One B-rep face of a CAD part: STEP entity #47.
In plain terms, the planar face has unit normal (-1, 0, 0).
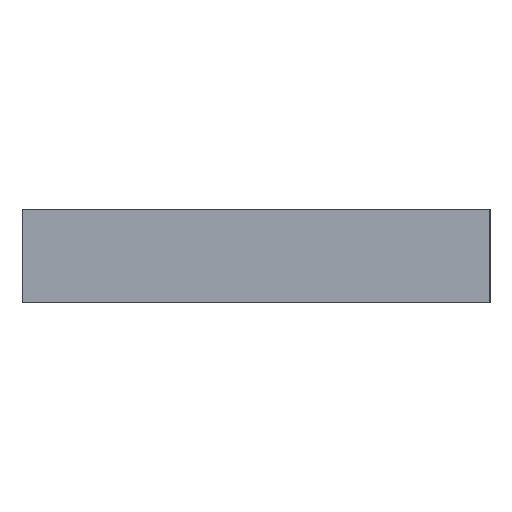
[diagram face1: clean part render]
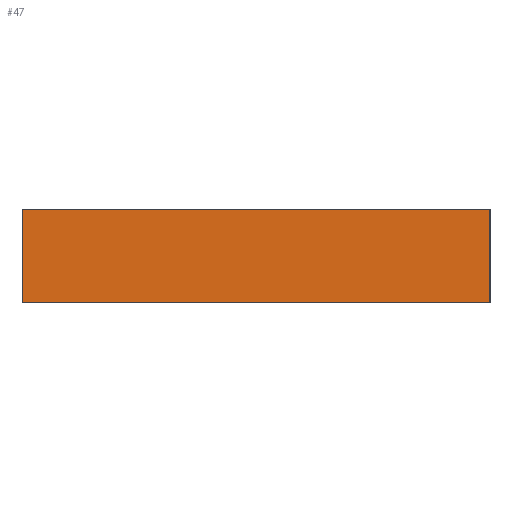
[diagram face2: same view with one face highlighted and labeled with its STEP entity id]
Its self-contained STEP definition (entity closure, numbers rounded to 3 decimals):
#47 = ADVANCED_FACE('',(#48),#62,.F.);
#48 = FACE_BOUND('',#49,.F.);
#49 = EDGE_LOOP('',(#50,#85,#113,#141));
#50 = ORIENTED_EDGE('',*,*,#51,.F.);
#51 = EDGE_CURVE('',#52,#54,#56,.T.);
#52 = VERTEX_POINT('',#53);
#53 = CARTESIAN_POINT('',(-23.167,-13.5,23.875));
#54 = VERTEX_POINT('',#55);
#55 = CARTESIAN_POINT('',(-23.167,-13.5,24.475));
#56 = SURFACE_CURVE('',#57,(#61,#73),.PCURVE_S1.);
#57 = LINE('',#58,#59);
#58 = CARTESIAN_POINT('',(-23.167,-13.5,23.875));
#59 = VECTOR('',#60,1.);
#60 = DIRECTION('',(0.,0.,1.));
#61 = PCURVE('',#62,#67);
#62 = PLANE('',#63);
#63 = AXIS2_PLACEMENT_3D('',#64,#65,#66);
#64 = CARTESIAN_POINT('',(-23.167,-13.5,23.875));
#65 = DIRECTION('',(1.,0.,0.));
#66 = DIRECTION('',(0.,0.,1.));
#67 = DEFINITIONAL_REPRESENTATION('',(#68),#72);
#68 = LINE('',#69,#70);
#69 = CARTESIAN_POINT('',(0.,0.));
#70 = VECTOR('',#71,1.);
#71 = DIRECTION('',(1.,0.));
#72 = ( GEOMETRIC_REPRESENTATION_CONTEXT(2) 
PARAMETRIC_REPRESENTATION_CONTEXT() REPRESENTATION_CONTEXT('2D SPACE',''
  ) );
#73 = PCURVE('',#74,#79);
#74 = PLANE('',#75);
#75 = AXIS2_PLACEMENT_3D('',#76,#77,#78);
#76 = CARTESIAN_POINT('',(-23.167,-13.5,23.875));
#77 = DIRECTION('',(0.,1.,0.));
#78 = DIRECTION('',(0.,0.,1.));
#79 = DEFINITIONAL_REPRESENTATION('',(#80),#84);
#80 = LINE('',#81,#82);
#81 = CARTESIAN_POINT('',(0.,0.));
#82 = VECTOR('',#83,1.);
#83 = DIRECTION('',(1.,0.));
#84 = ( GEOMETRIC_REPRESENTATION_CONTEXT(2) 
PARAMETRIC_REPRESENTATION_CONTEXT() REPRESENTATION_CONTEXT('2D SPACE',''
  ) );
#85 = ORIENTED_EDGE('',*,*,#86,.T.);
#86 = EDGE_CURVE('',#52,#87,#89,.T.);
#87 = VERTEX_POINT('',#88);
#88 = CARTESIAN_POINT('',(-23.167,-10.5,23.875));
#89 = SURFACE_CURVE('',#90,(#94,#101),.PCURVE_S1.);
#90 = LINE('',#91,#92);
#91 = CARTESIAN_POINT('',(-23.167,-13.5,23.875));
#92 = VECTOR('',#93,1.);
#93 = DIRECTION('',(0.,1.,0.));
#94 = PCURVE('',#62,#95);
#95 = DEFINITIONAL_REPRESENTATION('',(#96),#100);
#96 = LINE('',#97,#98);
#97 = CARTESIAN_POINT('',(0.,0.));
#98 = VECTOR('',#99,1.);
#99 = DIRECTION('',(0.,-1.));
#100 = ( GEOMETRIC_REPRESENTATION_CONTEXT(2) 
PARAMETRIC_REPRESENTATION_CONTEXT() REPRESENTATION_CONTEXT('2D SPACE',''
  ) );
#101 = PCURVE('',#102,#107);
#102 = PLANE('',#103);
#103 = AXIS2_PLACEMENT_3D('',#104,#105,#106);
#104 = CARTESIAN_POINT('',(-23.167,-13.5,23.875));
#105 = DIRECTION('',(0.,0.,1.));
#106 = DIRECTION('',(1.,0.,0.));
#107 = DEFINITIONAL_REPRESENTATION('',(#108),#112);
#108 = LINE('',#109,#110);
#109 = CARTESIAN_POINT('',(0.,0.));
#110 = VECTOR('',#111,1.);
#111 = DIRECTION('',(0.,1.));
#112 = ( GEOMETRIC_REPRESENTATION_CONTEXT(2) 
PARAMETRIC_REPRESENTATION_CONTEXT() REPRESENTATION_CONTEXT('2D SPACE',''
  ) );
#113 = ORIENTED_EDGE('',*,*,#114,.T.);
#114 = EDGE_CURVE('',#87,#115,#117,.T.);
#115 = VERTEX_POINT('',#116);
#116 = CARTESIAN_POINT('',(-23.167,-10.5,24.475));
#117 = SURFACE_CURVE('',#118,(#122,#129),.PCURVE_S1.);
#118 = LINE('',#119,#120);
#119 = CARTESIAN_POINT('',(-23.167,-10.5,23.875));
#120 = VECTOR('',#121,1.);
#121 = DIRECTION('',(0.,0.,1.));
#122 = PCURVE('',#62,#123);
#123 = DEFINITIONAL_REPRESENTATION('',(#124),#128);
#124 = LINE('',#125,#126);
#125 = CARTESIAN_POINT('',(0.,-3.));
#126 = VECTOR('',#127,1.);
#127 = DIRECTION('',(1.,0.));
#128 = ( GEOMETRIC_REPRESENTATION_CONTEXT(2) 
PARAMETRIC_REPRESENTATION_CONTEXT() REPRESENTATION_CONTEXT('2D SPACE',''
  ) );
#129 = PCURVE('',#130,#135);
#130 = PLANE('',#131);
#131 = AXIS2_PLACEMENT_3D('',#132,#133,#134);
#132 = CARTESIAN_POINT('',(-23.167,-10.5,23.875));
#133 = DIRECTION('',(0.,1.,0.));
#134 = DIRECTION('',(0.,0.,1.));
#135 = DEFINITIONAL_REPRESENTATION('',(#136),#140);
#136 = LINE('',#137,#138);
#137 = CARTESIAN_POINT('',(0.,0.));
#138 = VECTOR('',#139,1.);
#139 = DIRECTION('',(1.,0.));
#140 = ( GEOMETRIC_REPRESENTATION_CONTEXT(2) 
PARAMETRIC_REPRESENTATION_CONTEXT() REPRESENTATION_CONTEXT('2D SPACE',''
  ) );
#141 = ORIENTED_EDGE('',*,*,#142,.F.);
#142 = EDGE_CURVE('',#54,#115,#143,.T.);
#143 = SURFACE_CURVE('',#144,(#148,#155),.PCURVE_S1.);
#144 = LINE('',#145,#146);
#145 = CARTESIAN_POINT('',(-23.167,-13.5,24.475));
#146 = VECTOR('',#147,1.);
#147 = DIRECTION('',(0.,1.,0.));
#148 = PCURVE('',#62,#149);
#149 = DEFINITIONAL_REPRESENTATION('',(#150),#154);
#150 = LINE('',#151,#152);
#151 = CARTESIAN_POINT('',(0.6,0.));
#152 = VECTOR('',#153,1.);
#153 = DIRECTION('',(0.,-1.));
#154 = ( GEOMETRIC_REPRESENTATION_CONTEXT(2) 
PARAMETRIC_REPRESENTATION_CONTEXT() REPRESENTATION_CONTEXT('2D SPACE',''
  ) );
#155 = PCURVE('',#156,#161);
#156 = PLANE('',#157);
#157 = AXIS2_PLACEMENT_3D('',#158,#159,#160);
#158 = CARTESIAN_POINT('',(-23.167,-13.5,24.475));
#159 = DIRECTION('',(0.,0.,1.));
#160 = DIRECTION('',(1.,0.,0.));
#161 = DEFINITIONAL_REPRESENTATION('',(#162),#166);
#162 = LINE('',#163,#164);
#163 = CARTESIAN_POINT('',(0.,0.));
#164 = VECTOR('',#165,1.);
#165 = DIRECTION('',(0.,1.));
#166 = ( GEOMETRIC_REPRESENTATION_CONTEXT(2) 
PARAMETRIC_REPRESENTATION_CONTEXT() REPRESENTATION_CONTEXT('2D SPACE',''
  ) );
